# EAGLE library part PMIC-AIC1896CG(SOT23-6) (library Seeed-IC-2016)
310030104

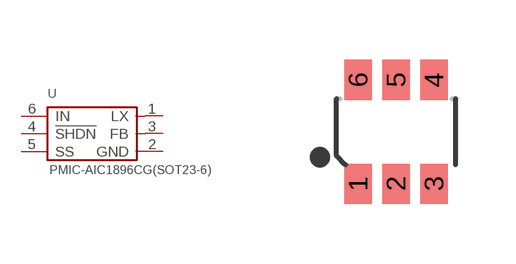
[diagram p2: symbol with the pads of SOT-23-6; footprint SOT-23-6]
Designator prefix U

## PMIC-AIC1896CG(SOT23-6) (MPN: AIC1896CG; VALUE: AIC1896CG-SOT23-6)  [SOT-23-6]
1  LX  out
2  GND  pwr
3  FB  in
4  !SHDN  in
5  SS  in
6  IN  in

## Footprint SOT-23-6 (pad centres in mm)
smd 0.69 x 1: 1 -0.95,-1.3; 2 0,-1.3; 3 0.95,-1.3; 4 0.95,1.3; 5 0,1.3; 6 -0.95,1.3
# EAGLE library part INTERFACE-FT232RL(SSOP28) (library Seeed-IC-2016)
310070022

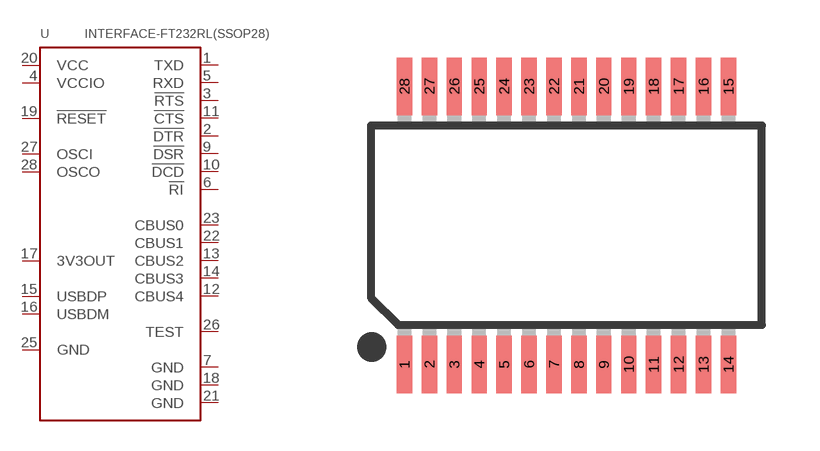
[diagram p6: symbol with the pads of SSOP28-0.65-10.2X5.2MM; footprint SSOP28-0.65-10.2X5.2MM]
Designator prefix U

## INTERFACE-FT232RL(SSOP28) (MPN: FT232RL; VALUE: FT232RL-SSOP28)  [SSOP28-0.65-10.2X5.2MM]
1  TXD  in
2  !DTR  in
3  !RTS  in
4  VCCIO  in
5  RXD  in
6  !RI  in
7  GND  in
9  !DSR  in
10  !DCD  in
11  !CTS  in
12  CBUS4  in
13  CBUS2  in
14  CBUS3  in
15  USBDP  in
16  USBDM  in
17  3V3OUT  in
18  GND  in
19  !RESET  in
20  VCC  in
21  GND  in
22  CBUS1  in
23  CBUS0  in
25  GND  in
26  TEST  in
27  OSCI  in
28  OSCO  in

## Footprint SSOP28-0.65-10.2X5.2MM (pad centres in mm)
Shrink Small Outline Package SSOP-28 http://www.ftdichip.com/Documents/DataSheets/DS_FT232R_v104.pdf
smd 0.4 x 1.5: 1 -4.225,-3.625; 2 -3.575,-3.625; 3 -2.925,-3.625; 4 -2.275,-3.625; 5 -1.625,-3.625; 6 -0.975,-3.625; 7 -0.325,-3.625; 8 0.325,-3.625; 9 0.975,-3.625; 10 1.625,-3.625; 11 2.275,-3.625; 12 2.925,-3.625; 13 3.575,-3.625; 14 4.225,-3.625; 15 4.225,3.625; 16 3.575,3.625; 17 2.925,3.625; 18 2.275,3.625; 19 1.625,3.625; 20 0.975,3.625; 21 0.325,3.625; 22 -0.325,3.625; 23 -0.975,3.625; 24 -1.625,3.625; 25 -2.275,3.625; 26 -2.925,3.625; 27 -3.575,3.625; 28 -4.225,3.625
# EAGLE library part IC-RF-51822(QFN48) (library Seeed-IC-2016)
310060026

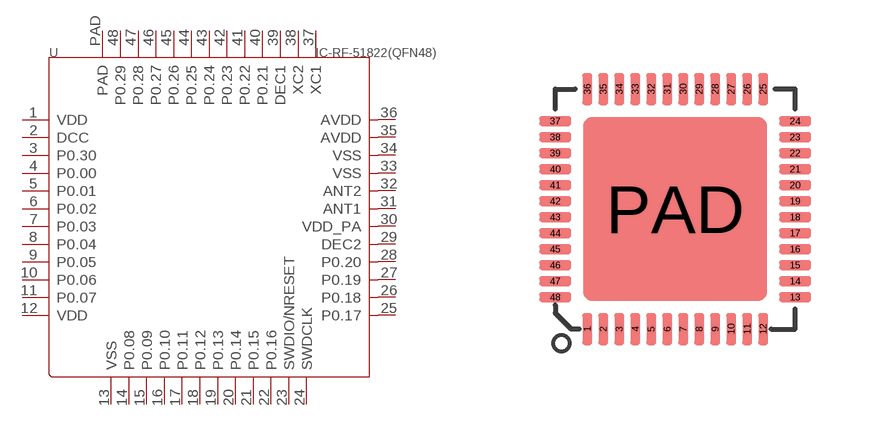
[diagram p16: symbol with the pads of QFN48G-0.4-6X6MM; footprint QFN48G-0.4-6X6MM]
Designator prefix U

## IC-RF-51822(QFN48) (MPN: RF-51822; VALUE: RF-51822)  [QFN48G-0.4-6X6MM]
1  VDD
2  DCC
3  P0.30
4  P0.00
5  P0.01
6  P0.02
7  P0.03
8  P0.04
9  P0.05
10  P0.06
11  P0.07
12  VDD
13  VSS
14  P0.08
15  P0.09
16  P0.10
17  P0.11
18  P0.12
19  P0.13
20  P0.14
21  P0.15
22  P0.16
23  SWDIO/NRESET
24  SWDCLK
25  P0.17
26  P0.18
27  P0.19
28  P0.20
29  DEC2
30  VDD_PA
31  ANT1
32  ANT2
33  VSS
34  VSS
35  AVDD
36  AVDD
37  XC1
38  XC2
39  DEC1
40  P0.21
41  P0.22
42  P0.23
43  P0.24
44  P0.25
45  P0.26
46  P0.27
47  P0.28
48  P0.29
PAD  PAD

## Footprint QFN48G-0.4-6X6MM (pad centres in mm)
smd 0.25 x 0.8: 1 -2.2,-3; 2 -1.8,-3; 3 -1.4,-3; 4 -1,-3; 5 -0.6,-3; 6 -0.2,-3; 7 0.2,-3; 8 0.6,-3; 9 1,-3; 10 1.4,-3; 11 1.8,-3; 12 2.2,-3; 25 2.2,3; 26 1.8,3; 27 1.4,3; 28 1,3; 29 0.6,3; 30 0.2,3; 31 -0.2,3; 32 -0.6,3; 33 -1,3; 34 -1.4,3; 35 -1.8,3; 36 -2.2,3
smd 0.8 x 0.25: 13 3,-2.2; 14 3,-1.8; 15 3,-1.4; 16 3,-1; 17 3,-0.6; 18 3,-0.2; 19 3,0.2; 20 3,0.6; 21 3,1; 22 3,1.4; 23 3,1.8; 24 3,2.2; 37 -3,2.2; 38 -3,1.8; 39 -3,1.4; 40 -3,1; 41 -3,0.6; 42 -3,0.2; 43 -3,-0.2; 44 -3,-0.6; 45 -3,-1; 46 -3,-1.4; 47 -3,-1.8; 48 -3,-2.2
smd 4.6 x 4.6: PAD 0,0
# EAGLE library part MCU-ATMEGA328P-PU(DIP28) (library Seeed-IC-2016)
310010051

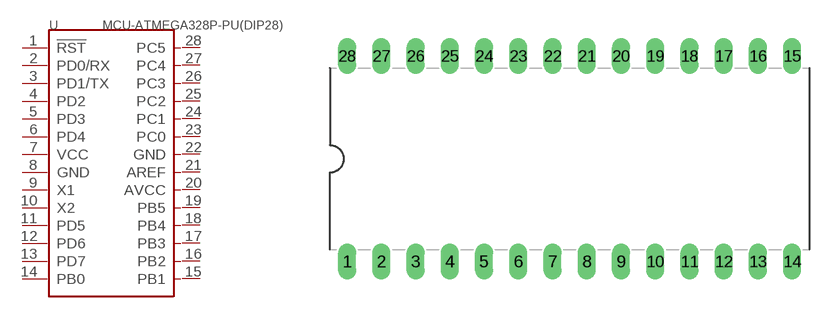
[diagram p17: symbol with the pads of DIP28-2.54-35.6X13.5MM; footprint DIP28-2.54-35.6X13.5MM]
Designator prefix U

## MCU-ATMEGA328P-PU(DIP28) (MPN: ATMEGA328P-PU; VALUE-DIP28: ATMEGA328P-PU)  [DIP28-2.54-35.6X13.5MM]
1  !RST
2  PD0/RX
3  PD1/TX
4  PD2
5  PD3
6  PD4
7  VCC
8  GND
9  X1
10  X2
11  PD5
12  PD6
13  PD7
14  PB0
15  PB1
16  PB2
17  PB3
18  PB4
19  PB5
20  AVCC
21  AREF
22  GND
23  PC0
24  PC1
25  PC2
26  PC3
27  PC4
28  PC5

## Footprint DIP28-2.54-35.6X13.5MM (pad centres in mm)
drill 0.813 long: 1 -16.51,-7.62; 2 -13.97,-7.62; 3 -11.43,-7.62; 4 -8.89,-7.62; 5 -6.35,-7.62; 6 -3.81,-7.62; 7 -1.27,-7.62; 8 1.27,-7.62; 9 3.81,-7.62; 10 6.35,-7.62; 11 8.89,-7.62; 12 11.43,-7.62; 13 13.97,-7.62; 14 16.51,-7.62; 15 16.51,7.62; 16 13.97,7.62; 17 11.43,7.62; 18 8.89,7.62; 19 6.35,7.62; 20 3.81,7.62; 21 1.27,7.62; 22 -1.27,7.62; 23 -3.81,7.62; 24 -6.35,7.62; 25 -8.89,7.62; 26 -11.43,7.62; 27 -13.97,7.62; 28 -16.51,7.62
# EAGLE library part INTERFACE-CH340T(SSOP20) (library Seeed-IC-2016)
310070026

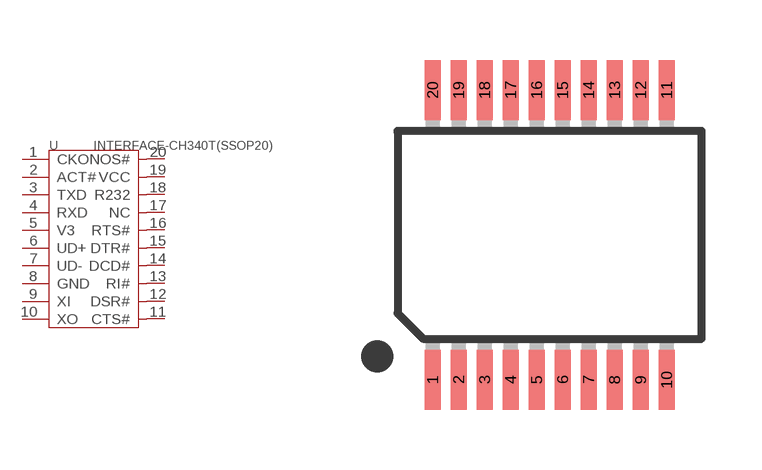
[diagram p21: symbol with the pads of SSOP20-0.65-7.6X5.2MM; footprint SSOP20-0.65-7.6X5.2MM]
Designator prefix U

## INTERFACE-CH340T(SSOP20) (MPN: CH340T; VALUE: CH340T-SSOP20)  [SSOP20-0.65-7.6X5.2MM]
1  CKO  out
2  ACT#  out
3  TXD  out
4  RXD  in
5  V3  sup
6  UD+
7  UD-
8  GND  sup
9  XI  in
10  XO  out
11  CTS#  in
12  DSR#  in
13  RI#  in
14  DCD#  in
15  DTR#  out
16  RTS#  out
17  NC  nc
18  R232  in
19  VCC  sup
20  NOS#  sup

## Footprint SSOP20-0.65-7.6X5.2MM (pad centres in mm)
Shrink Small Outline Package package type SS
smd 0.4 x 1.5: 1 -2.925,-3.625; 2 -2.275,-3.625; 3 -1.625,-3.625; 4 -0.975,-3.625; 5 -0.325,-3.625; 6 0.325,-3.625; 7 0.975,-3.625; 8 1.625,-3.625; 9 2.275,-3.625; 10 2.925,-3.625; 11 2.925,3.625; 12 2.275,3.625; 13 1.625,3.625; 14 0.975,3.625; 15 0.325,3.625; 16 -0.325,3.625; 17 -0.975,3.625; 18 -1.625,3.625; 19 -2.275,3.625; 20 -2.925,3.625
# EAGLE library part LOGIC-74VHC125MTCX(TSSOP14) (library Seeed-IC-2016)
310050042

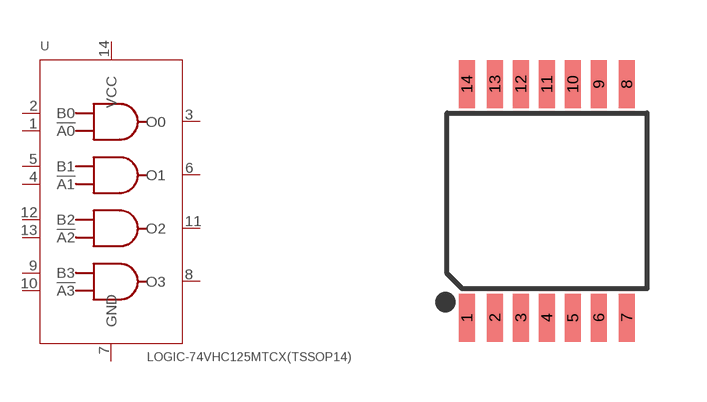
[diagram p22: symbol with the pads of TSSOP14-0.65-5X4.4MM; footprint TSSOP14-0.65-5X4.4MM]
Designator prefix U

## LOGIC-74VHC125MTCX(TSSOP14) (MPN: 74VHC125MTCX; VALUE: 74VHC125MTCX-TSSOP14)  [TSSOP14-0.65-5X4.4MM]
1  !A0  sup
2  B0
3  O0
4  !A1  sup
5  B1
6  O1
7  GND  sup
8  O3
9  B3
10  !A3
11  O2
12  B2
13  !A2  in
14  VCC  pwr

## Footprint TSSOP14-0.65-5X4.4MM (pad centres in mm)
smd 0.4 x 1.2: 1 -2,-2.925; 2 -1.3,-2.925; 3 -0.65,-2.925; 4 0,-2.925; 5 0.65,-2.925; 6 1.3,-2.925; 7 2,-2.925; 8 2,2.925; 9 1.3,2.925; 10 0.65,2.925; 11 0,2.925; 12 -0.65,2.925; 13 -1.3,2.925; 14 -2,2.925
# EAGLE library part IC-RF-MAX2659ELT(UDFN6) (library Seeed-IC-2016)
310060024

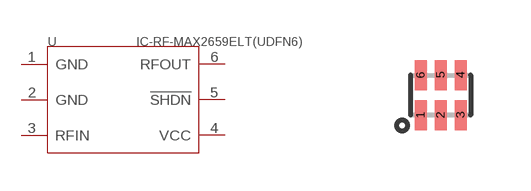
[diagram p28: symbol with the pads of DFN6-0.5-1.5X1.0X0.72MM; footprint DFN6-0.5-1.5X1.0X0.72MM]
Designator prefix U

## IC-RF-MAX2659ELT(UDFN6) (MPN: MAX2659ELT; VALUE: MAX2659ELT)  [DFN6-0.5-1.5X1.0X0.72MM]
1  GND  sup
2  GND  sup
3  RFIN
4  VCC
5  !SHDN
6  RFOUT

## Footprint DFN6-0.5-1.5X1.0X0.72MM (pad centres in mm)
smd 0.3 x 0.75: 1 -0.5,-0.5; 2 0,-0.5; 3 0.5,-0.5; 4 0.5,0.5; 5 0,0.5; 6 -0.5,0.5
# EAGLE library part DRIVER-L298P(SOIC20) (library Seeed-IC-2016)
310040018

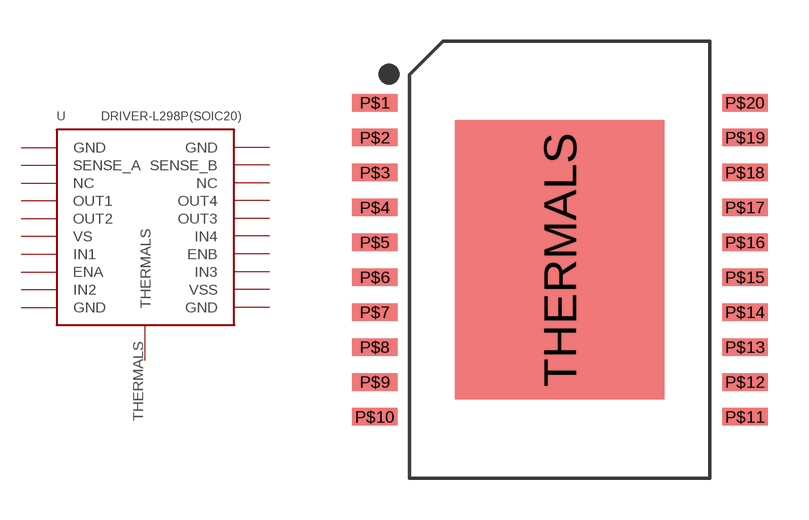
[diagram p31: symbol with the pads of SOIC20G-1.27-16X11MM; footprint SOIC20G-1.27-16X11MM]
Designator prefix U

## DRIVER-L298P(SOIC20) (MPN: L298P; VALUE: L298P-SOIC20)  [SOIC20G-1.27-16X11MM]
P$1  GND
P$2  SENSE_A
P$3  NC
P$4  OUT1
P$5  OUT2
P$6  VS
P$7  IN1
P$8  ENA
P$9  IN2
P$10  GND
P$11  GND
P$12  VSS
P$13  IN3
P$14  ENB
P$15  IN4
P$16  OUT3
P$17  OUT4
P$18  NC
P$19  SENSE_B
P$20  GND
THERMALS  THERMALS

## Footprint SOIC20G-1.27-16X11MM (pad centres in mm)
smd 1.651 x 0.635: P$1 -6.731,5.715; P$2 -6.731,4.445; P$3 -6.731,3.175; P$4 -6.731,1.905; P$5 -6.731,0.635; P$6 -6.731,-0.635; P$7 -6.731,-1.905; P$8 -6.731,-3.175; P$9 -6.731,-4.445; P$10 -6.731,-5.715; P$11 6.731,-5.715; P$12 6.731,-4.445; P$13 6.731,-3.175; P$14 6.731,-1.905; P$15 6.731,-0.635; P$16 6.731,0.635; P$17 6.731,1.905; P$18 6.731,3.175; P$19 6.731,4.445; P$20 6.731,5.715
smd 7.62 x 10.16: THERMALS 0,0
